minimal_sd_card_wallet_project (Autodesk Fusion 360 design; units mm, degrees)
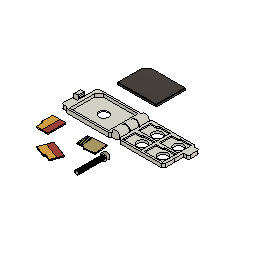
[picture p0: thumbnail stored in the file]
parameter "msd_relief" = 0.15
